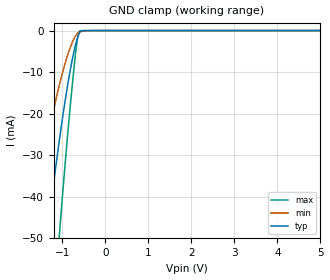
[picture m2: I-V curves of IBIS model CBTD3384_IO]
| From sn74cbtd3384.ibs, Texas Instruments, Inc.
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[Model]   CBTD3384_IO
Model_type  Terminator
| variable   typ   min   max
C_comp   4.30pF   3.71pF   4.90pF
| C_tri-state   4.30pF   3.71pF   4.90pF
[Temperature Range]   40   100   -40
| Ambient temperature   25   85   -40
[Voltage range]   5   4.5   5.5
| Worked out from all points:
|   GND clamp passes 1 mA (typ) near -0.62 V on its own axis
[GND Clamp]
| CBTD3384_IO
|   Voltage   I(typ)   I(min)   I(max)
-5V       -425.8mA   -258.3mA   -721.6mA
-1.755V   -86.54mA   -49.2mA    -151.9mA
-1.7V     -81.29mA   -45.94mA   -143.2mA
-1.345V   -49.06mA   -26.3mA    -88.71mA
-1.3V     -45.22mA   -24.02mA   -82.12mA
-1.085V   -27.92mA   -13.97mA   -51.96mA
-1.045V   -24.93mA   -12.29mA   -46.65mA
-865mV    -12.68mA   -5.668mA   -24.26mA
-710mV    -4.351mA   -1.667mA   -7.594mA
-645mV    -1.832mA   -681.3uA   -2.047mA
-590mV    -430.5uA   -303.4uA   -53.5uA
5V        237.8pA    477pA      216.5pA
